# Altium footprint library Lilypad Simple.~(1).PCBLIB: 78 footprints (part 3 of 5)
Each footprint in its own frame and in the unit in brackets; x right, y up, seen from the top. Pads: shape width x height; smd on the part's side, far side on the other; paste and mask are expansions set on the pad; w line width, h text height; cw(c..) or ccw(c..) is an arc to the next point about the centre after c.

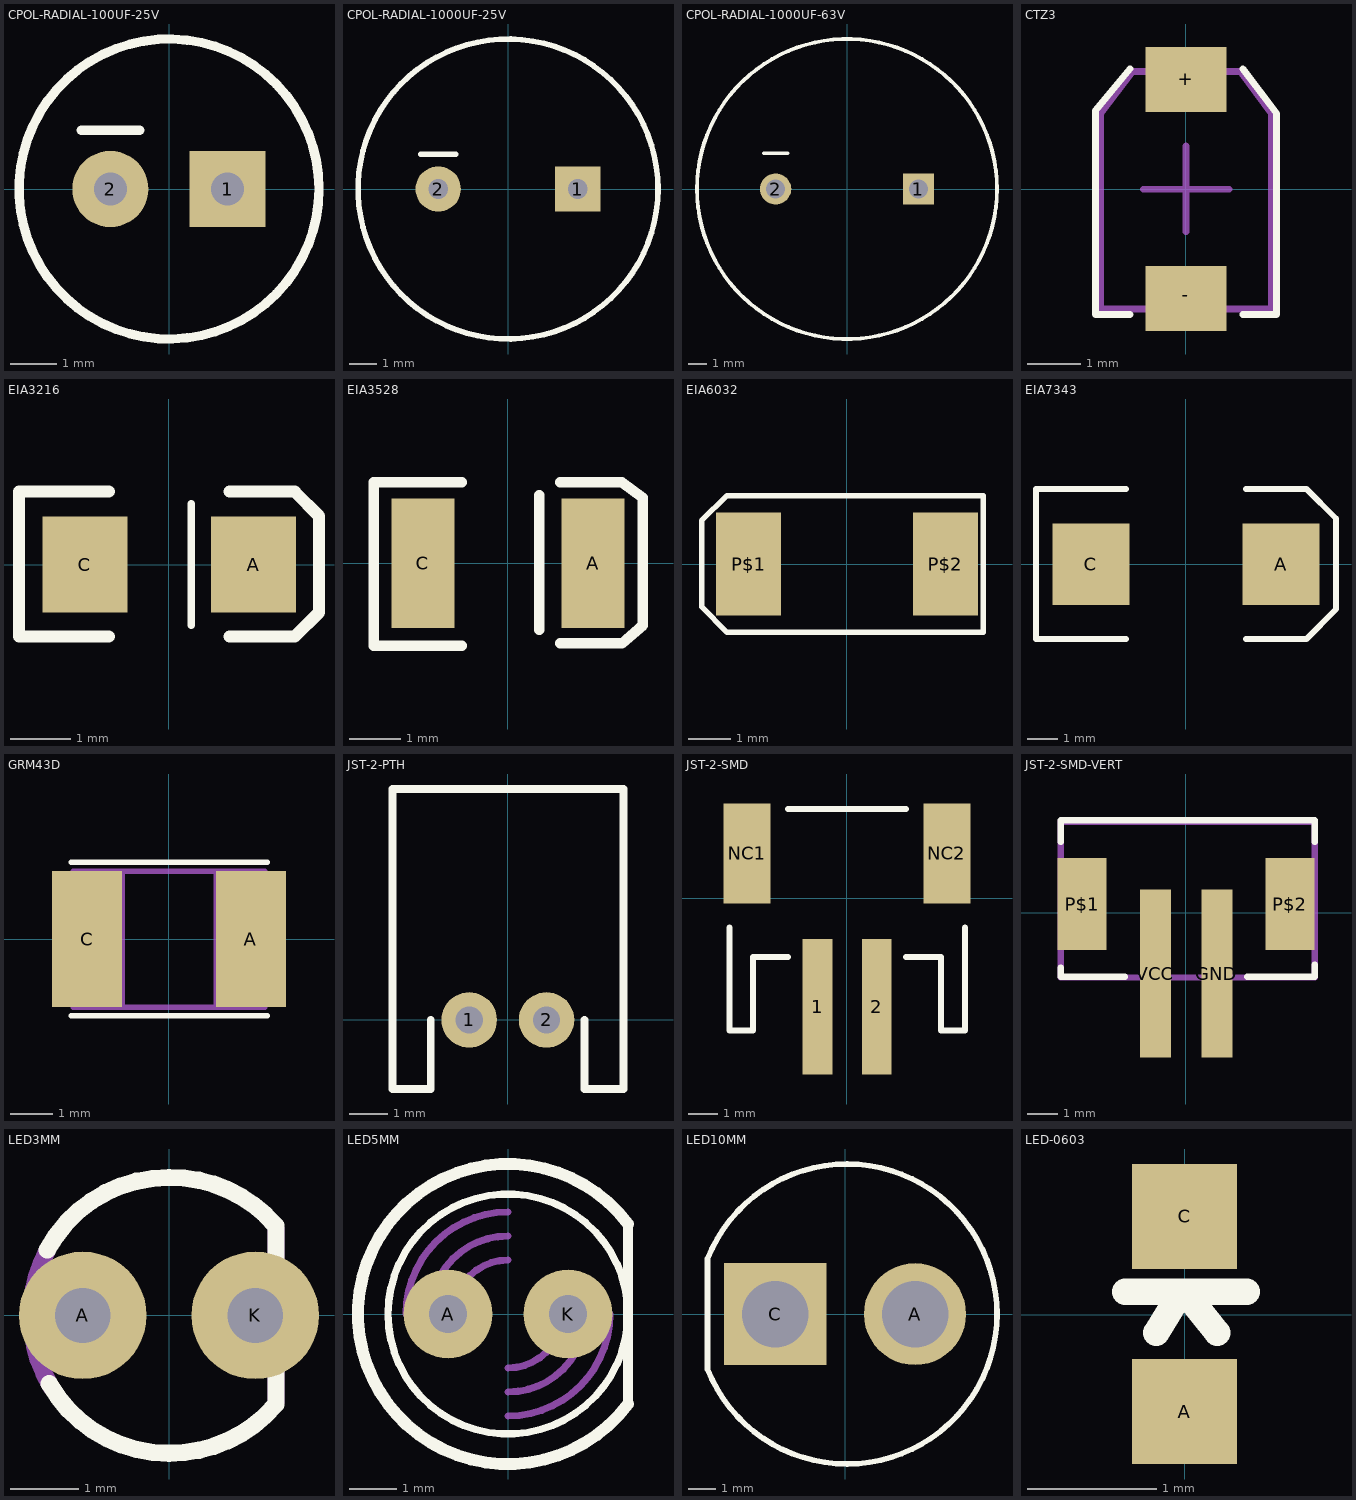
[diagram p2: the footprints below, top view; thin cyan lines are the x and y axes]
## CPOL-RADIAL-100UF-25V [mil]
pads (2):
  rect 65x65 hole 28: 1(50,0)
  round 65 hole 28: 2(-50,0)
Top Overlay:
  circle w8: c0,0 r128
  lines w8: -75,50 -25,50

## CPOL-RADIAL-1000UF-25V [mil]
pads (2):
  rect 65x65 hole 28: 1(100,0)
  round 65 hole 28: 2(-100,0)
Top Overlay:
  circle w8: c0,0 r215
  lines w8: -125,50 -75,50

## CPOL-RADIAL-1000UF-63V [mil]
pads (2):
  rect 65x65 hole 40: 1(150,0)
  round 66 hole 40: 2(-150,0)
Top Overlay:
  circle w8: c0,0 r315
  lines w8: -175,75 -125,75

## CTZ3 [mil]
pads (2):
  rect 60x48 smd: +(0,81) -(0,-80.71)
Top Overlay:
  lines w5: -41.34,-92.52 -66.93,-92.52 -66.93,58 -41.34,89 ; 42,-92.52 67,-92.52 67,56 42,89
Courtyard Bottom:
  lines w5: -31.5,0 32,0 ; -19.68,0 20,0 ; 0,-31.5 0,32 ; -62.99,-88.58 -62.99,56 -39.37,87 40,87 63,56 63,-88.58 -62.99,-88.58

## EIA3216 [mil]
pads (2):
  rect 56x63 smd: A(56,0) C(-55.12,0)
Top Overlay:
  lines w5: 15,-40 15,40
  lines w8: -39.37,-47.24 -98.43,-47.24 -98.43,48 -39.37,48 ; 40,-47.24 83,-47.24 99,-31.5 99,32 83,48 40,48

## EIA3528 [mil]
pads (2):
  rect 48x99 smd: A(65,0) C(-64.96,0)
Top Overlay:
  lines w8: -35.43,-62.99 -102.36,-62.99 -102.36,62 -35.43,62 ; 24,-50.63 24,52 ; 40,-61.02 87,-61.02 103,-47.24 103,50 87,62 40,62

## EIA6032 [mil]
pads (2):
  rect 60x95 smd: P$1(-90.55,0) P$2(91,0)
Top Overlay:
  lines w5: -133.86,-39.37 -133.86,40 -110.24,63 126,63 126,-62.99 -110.24,-62.99 -133.86,-39.37

## EIA7343 [mil]
pads (2):
  rect 101x107 smd: A(125,0) C(-124.8,0)
Top Overlay:
  lines w8: -78.74,-98.43 -196.85,-98.43 -196.85,99 -78.74,99 ; 79,-98.43 158,-98.43 197,-59.06 197,60 158,99 79,99

## GRM43D [mil]
pads (2):
  rect 65x126 smd: A(76,0) C(-75.87,0)
Top Overlay:
  lines w5: -90.55,-70.87 91,-70.87 ; -90.55,71 91,71
Courtyard Bottom:
  rectangle: -86.61,-62.99 -43.31,63
  rectangle: 44,-62.99 87,63
  lines w5: -43.31,-62.99 -88.58,-62.99 -88.58,63 -43.31,63 ; -43.31,-62.99 44,-62.99 ; -43.31,-62.99 -43.31,63 ; -43.31,63 44,63 ; 44,-62.99 89,-62.99 89,63 44,63 ; 44,-62.99 44,63

## JST-2-PTH [mil]
pads (2):
  round 57 hole 28: 1(-39.37,0) 2(40,0)
Top Overlay:
  lines w8: -78.74,0 -78.74,-70.87 -118.11,-70.87 -118.11,237 119,237 119,-70.87 79,-70.87 79,0
Courtyard Bottom:
  text "+" at 24,28 h77.5
  text "-" at -55.12,28 h77.5

## JST-2-SMD [mil]
pads (4):
  rect 40x182 smd: 1(-39.37,-145.67) 2(40,-145.67)
  rect 63x134 smd: NC1(-133.86,60) NC2(134,60)
Top Overlay:
  lines w8: -157.48,-39.37 -157.48,-177.17 -125.98,-177.17 -125.98,-78.74 -78.74,-78.74 ; -78.74,119 79,119 ; 79,-78.74 126,-78.74 126,-177.17 158,-177.17 158,-39.37
Courtyard Bottom:
  text "+" at 85,-175 h77.5
  text "-" at -115,-175 h77.5

## JST-2-SMD-VERT [mil]
pads (4):
  rect 40x217 smd: GND(40,-78.74) VCC(-39.37,-78.74)
  rect 63x119 smd: P$1(-133.86,11) P$2(134,11)
Top Overlay:
  lines w8: -161.42,-70.87 -161.42,-82.68 -78.74,-82.68 ; -161.42,91 -161.42,119 166,119 166,91 ; 79,-82.68 166,-82.68 166,-66.93
Courtyard Bottom:
  lines w8: -161.42,-83.86 166,-83.86 166,117 -161.42,117 -161.42,-83.86

## LED3MM [mil]
pads (2):
  round 74 hole 32: A(-50,0) K(50,0)
Top Overlay:
  lines w10: -70.59,38 cw(c-0.29,0.18) 0,80 cw(c1.11,-0.19) 62,52 ; -69.46,-39.69 ccw(c0,0) 0,-80 ccw(c0.47,1) 62,-51.68 ; 62,-51 62,-33 ; 62,31 62,51
Courtyard Bottom:
  lines w10: -70.44,38 ccw(c0.14,0.04) -80,0 ccw(c0,0) -68.13,-41.93 ; 62,-50 62,50

## LED5MM [mil]
pads (2):
  round 74 hole 32: A(-50,0) K(50,0)
Top Overlay:
  circle w6: c0,0 r100
  lines w8: 100,-75 100,75
  lines w10: 100,-75 cw(c0,0) 100,75
Courtyard Bottom:
  lines w6: -85,0 cw(c0,0) 0,85 ; -65,0 cw(c0,0) 0,65 ; -45,0 cw(c0,0) 0,45 ; 0,-85 ccw(c0,0) 85,0 ; 0,-65 ccw(c0,0) 65,0 ; 0,-45 ccw(c0,0) 45,0

## LED10MM [mil]
pads (2):
  round 146 hole 95: A(100,0)
  rect 146x146 hole 95: C(-100,0)
Top Overlay:
  lines w8: -196.85,-78.74 ccw(c2.67,0.13) -196.85,79 -196.85,-78.74
Courtyard Bottom:
  text "L" at 85,100 h62
  text "S" at -115,100 h62

## LED-0603 [mil]
pads (2):
  rect 32x32 smd: A(0,-29.53) C(0,30)
Top Overlay:
  lines w8: -18.11,7 0,7 ; -8.6,-5.51 -1,7 ; 10,-5.51 0,7 ; 19,7 0,7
